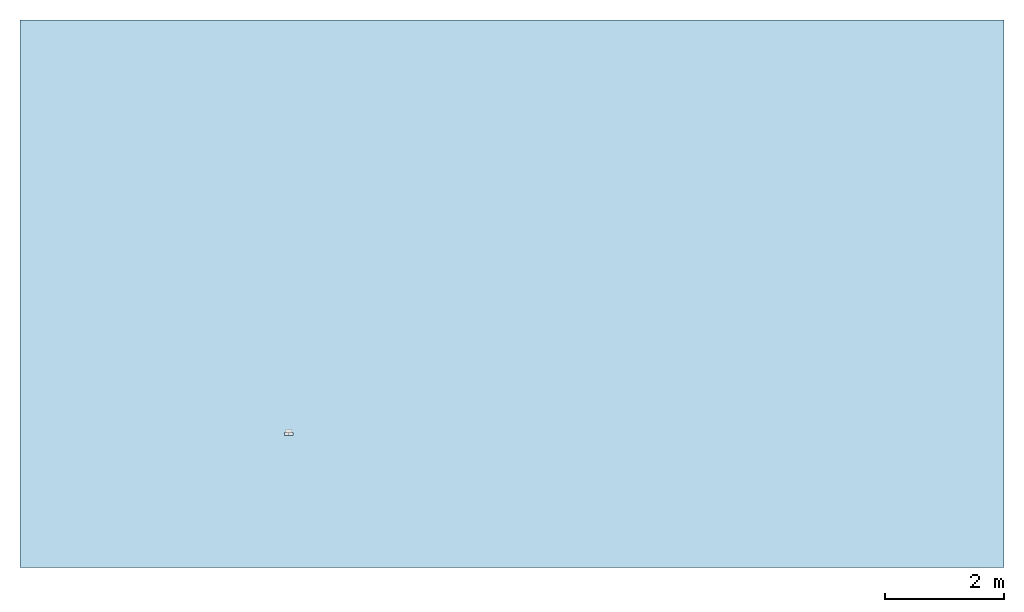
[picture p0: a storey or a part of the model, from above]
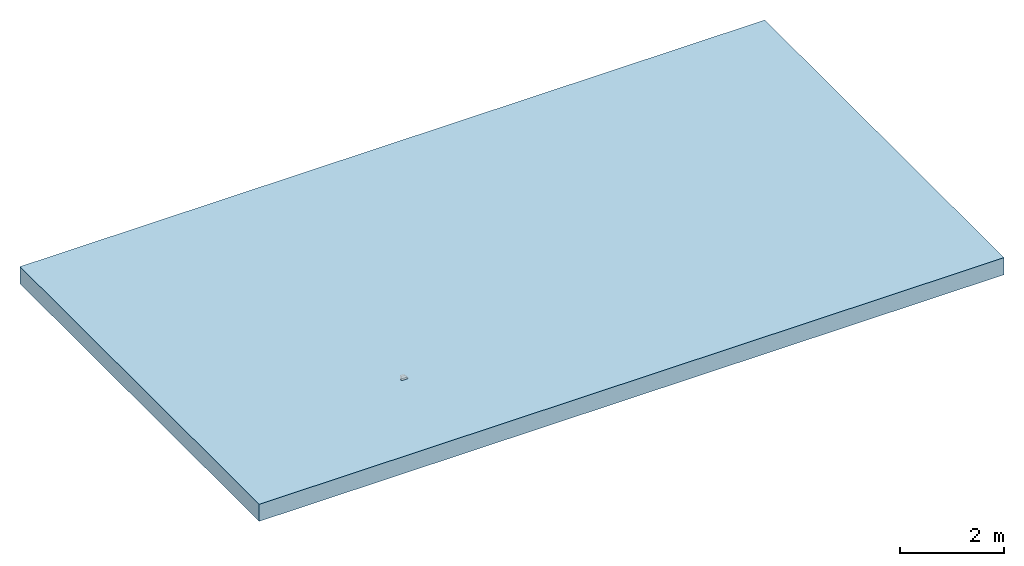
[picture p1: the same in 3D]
Properties of the parts of a building model (IFC2X3)

# File
Description: ViewDefinition [CoordinationView]
File name: 7942 - LH inlet-outlet end cap.ifc
Time: 2013-09-02T12:34:38
Written by: Autodesk Revit 2013
Made in: 20120221_2030(x64)

# IfcProject, Project Number
LongName: Project Name; Phase: Project Status

# IfcSite, Default
RefLatitude: 42, 21, 30, 344238; RefLongitude: -71, -3, -35, -194702; RefElevation: 0 mm

# IfcBuilding
Pset_BuildingCommon - NumberOfStoreys: 1
Other - Project Address: ## Street City, State Zip; Client Name: Owner; Project Number: Project Number; Project Name: Project Name; Project Status: Project Status; Project Issue Date: Issue Date

# IfcBuildingStorey, Level 1
LongName: Level 1; Elevation: 0 mm
Constraints - Elevation Base: 0; Elevation: 0 mm
Graphics - Line Pattern: Center; Color: 0; Line Weight: 1; Symbol at End 1 Default: no; Symbol at End 2 Default: yes; Symbol: M_Level Head - Circle: M_Level Head - Circle
Dimensions - Computation Height: 0 mm
Identity Data - Name: Level 1; Building Story: yes; Structural: no

# IfcBuildingElementProxy: 7942 - LH inlet/outlet end cap, Civil-Drainage-Channel-ACO-KerbDrain-SP280:7942 - LH inlet/outlet end cap:7942 - LH inlet/outlet end cap:311063
In: Level 1
Material: Orange, ACO Polymer Concrete.
Other - Revision: 1; CreatedBy: www.aco.co.uk
Phasing - Phase Created: New Construction
Constraints - Level: Level: Level 1; Moves With Nearby Elements: no
Dimensions - Volume: 1648380 mm3; Void Length: 50 mm; Void Depth: -180 mm; Endcap void: 230 mm; AccessDepth: 2000 mm; Void Width: 150 mm; Access hole: 2 mm
Pset_BuildingElementProxyCommon - Reference: 7942 - LH inlet/outlet end cap
General - SerialNumber: 0.000000; TagNumber: 0.000000
Identity Data - OmniClass Title: Rainwater Removal; Manufacturer: ACO Technologies plc - ACO Water Management Division; Fax: +44 (0)1462 815895; URL: www.aco.co.uk; Assembly Description: Rain Water Drainage; Type Comments: ACO KerbDrain SP280 splayed LH inlet / outlet end cap; Model Description: Combined kerb and drainage system; Product Code: 7942; Assembly Code: D2040; Cost: 0; e-mail Sales: customersupport@aco.co.uk; Maintenance guidelines: http://www.aco.co.uk/download.php?id=120; Price: POA - contact ACO; Product Page URL: http://www.aco.co.uk/product_detail.php?id=3; OmniClass Number: 23.70.50.24; Address: ACO Business Park, Hitchin Road, Shefford, Bedfordshire, United Kingdom SG17 5TE; Telephone: +44 (0)1462 816666; Installation guidelines: http://www.aco.co.uk/download.php?id=120; Product brochure: http://www.aco.co.uk/download.php?id=120; Model: ACO KerbDrain SP280; e-mail Technical: technical@aco.co.uk
Green Building Properties - Channel Recycled Material Content: N/A; Access Cover/Frame Recycled Material Content: N/A; End Cap Recycled Material Content: 20% minimum; Channel Recyclable: N/A; Access Cover/Frame Recyclable: N/A; End Cap Recyclable: Fully recyclable
Data - Invert Depth: N/A; Concrete Surround Volume - Load Class A 15 - D 400 - Grass or Asphalt Pavement: N/A; Concrete Surround Volume - Load Class A 15 - D 400 - Concrete Pavement: N/A; Drainage Slot Intake area: N/A; ACO Hydraulic Design Software: N/A; Channel C.S.A: N/A; Installation - Concrete Grade: N/A; Product Dimensions: 50mm x 150mm x 280mm (LxWxH); Hydraulic Performance: N/A; Product Weight: 3.4 Kg; Connection Pipe O.D: Ø110mm; Load Class: N/A; Product Standard: N/A; Drainage Slot Width: N/A
Construction - Centre Stone: no; RH inlet/outlet end cap: no; LH drop kerb: no; LH transition unit: no; SP280 - 1000: no; SP280-500: no; Closing end cap: no; perforated centre stone: no; LH inlet/outlet end cap: yes; Access Unit: no; RH transition unit: no; RH drop kerb: no
Materials and Finishes - Connection Pipe Material: PVCu; Channel Colour: N/A; Access Cover/Frame Finish: N/A; Access Cover/Frame Colour: N/A; Channel Material: N/A; Access Cover/Frame Material: N/A; Connection Pipe Material Colour: Brown; End Cap Material: Vienite® Synthetic Resin Concrete; End Cap Colour: Grey

# IfcOpeningElement: Recess (2)
In: Level 1
Dimensions - Perimeter: 51360 mm; Thickness: 400 mm; Volume: 60586181707 mm3; Area: 151470000 mm2
Constraints - Height Offset From Level: 0 mm; Room Bounding: yes; Related to Mass: no; Level: Level: Level 1
Phasing - Phase Created: New Construction
Structural - Structural: no; Enable Analytical Model: no
Analytical Properties - Roughness: 1; Absorptance: 0.1
Construction - Function: 0; Default Thickness: 400 mm
Graphics - Coarse Scale Fill Color: 0
Materials and Finishes - Structural Material: Plant

# IfcSlab: Floor:Generic Floor - 400mm, Floor:Generic Floor - 400mm:193825
In: Level 1
PredefinedType: FLOOR; Material: Plant 400 mm
Dimensions - Perimeter: 51360 mm; Thickness: 400 mm; Volume: 60586181707 mm3; Area: 151470000 mm2
Constraints - Height Offset From Level: 0 mm; Room Bounding: yes; Related to Mass: no; Level: Level: Level 1
Phasing - Phase Created: New Construction
Structural - Structural: no; Enable Analytical Model: no
Pset_SlabCommon - Reference: Generic Floor - 400mm; IsExternal: no; LoadBearing: yes
Analytical Properties - Roughness: 1; Absorptance: 0.1
Construction - Function: 0; Default Thickness: 400 mm
Graphics - Coarse Scale Fill Color: 0
Materials and Finishes - Structural Material: Plant
